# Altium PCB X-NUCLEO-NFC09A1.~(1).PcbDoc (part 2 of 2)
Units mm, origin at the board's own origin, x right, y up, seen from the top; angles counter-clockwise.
Board outline 103.96 x 54 mm, 4 copper layers (Top Layer, F2-GND, F3, Bottom Layer), stack 1.17 mm thick; 124 components, 76 nets, 282 pads, 390 vias.

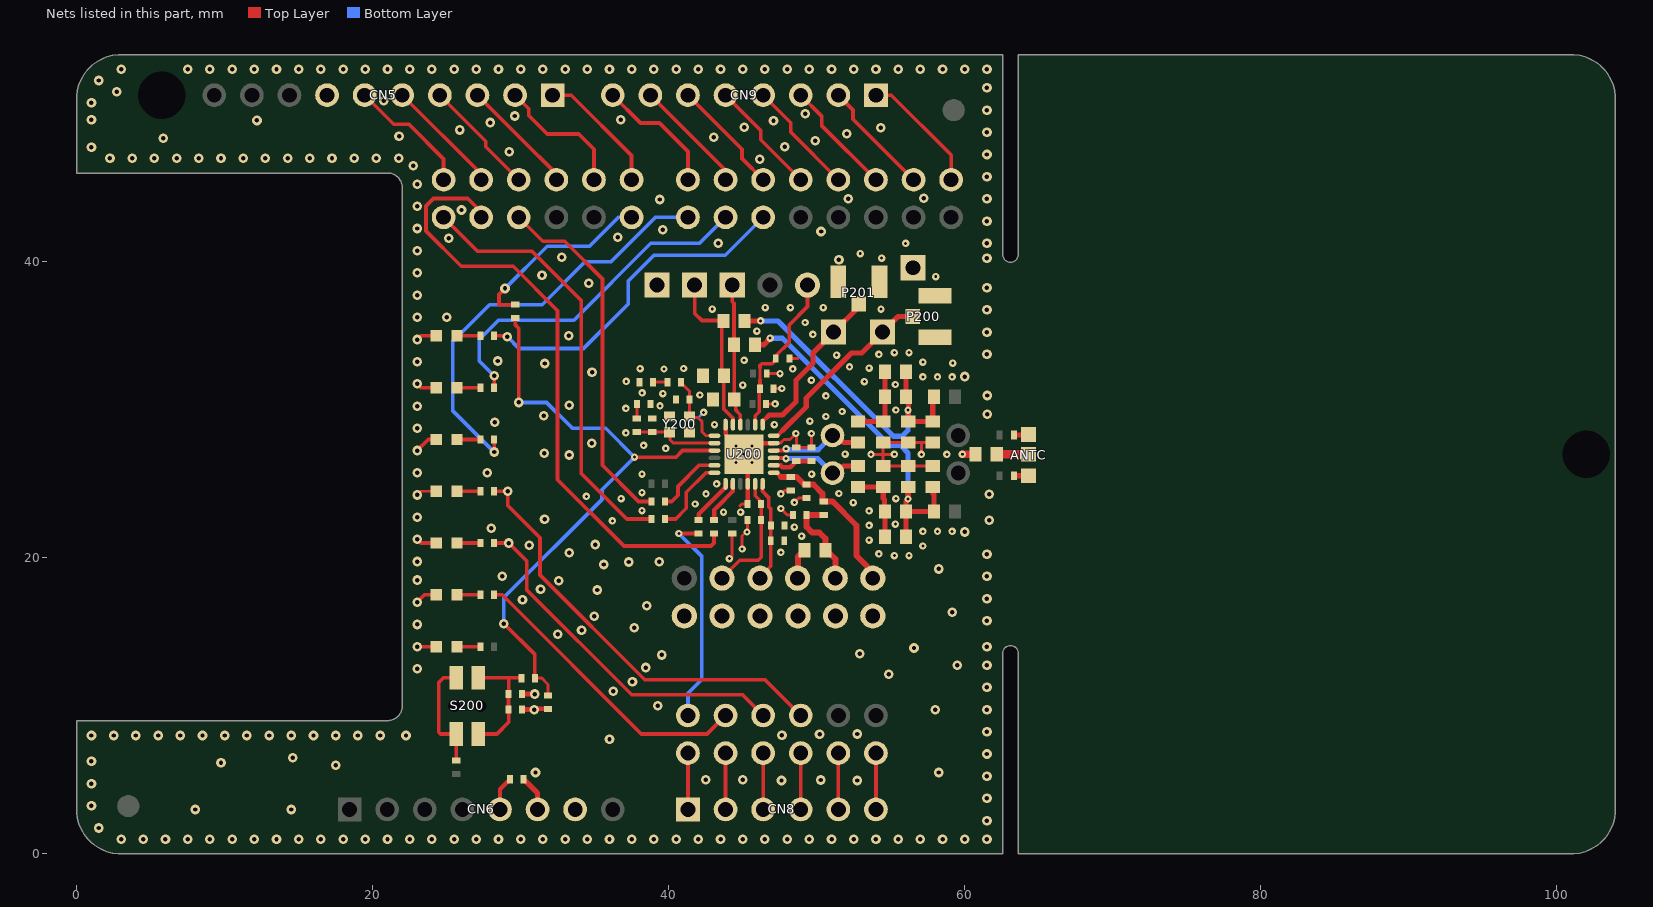
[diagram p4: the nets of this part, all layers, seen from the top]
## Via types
v1: diameter 0.65, hole 0.3, Top Layer to Bottom Layer, 272 vias
v2: diameter 0.5, hole 0.2, Top Layer to Bottom Layer, 108 vias
v3: diameter 1, hole 0.5, Top Layer to Bottom Layer, 10 vias

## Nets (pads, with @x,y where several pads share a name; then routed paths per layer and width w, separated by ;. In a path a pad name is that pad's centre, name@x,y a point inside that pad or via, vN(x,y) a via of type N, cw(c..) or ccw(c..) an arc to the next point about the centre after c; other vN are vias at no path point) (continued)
GND: C100.2 C200.2 C201.2 C202.2 C203.2 C204.2 C205.2 C206.2 C207.2 C208.2 C209.2 C210.2 C211.2 C212.2 C213.2 C214.2 C215.2 C216.1 C217.2 C218.2 C300.1 C304.2 C305.2 C306.2 C307.1 C308.1 C309.1 C313.2 CN5.7 CN6.6 CN6.7 LED100.2 LED101.2 LED102.2 LED103.2 LED104.2 LED105.2 LED106.2 P200.2 P200.3 P201.2 P201.3 R210.1 R212.2 R304.1 TP201.1 TP210.1 TP211.1 TP212.1 TP213.1 TP214.1 TP218.1 TP219.1 U200.4 U200.11 U200.18 U200.25 Y200.2 Y200.4 | length 48.4
  Top Layer w0.2: v1(23,24.25) 23.25,24.5 LED103.2@24.302,24.5 ; v2(44.1,19.95) 44.21,19.95 44.29,20.03 C212.2@44.29,21.636 ; 44.8,23.5 44.94,23.64 C210.2@45.333,23.64 ; v2(44.958,20.6) 44.958,21.481 45.323,21.846 C211.2@45.323,22.55 ; v2(45.09,27) U200.25@45.34,26.75 ; C200.2@46.572,30.4 v2(47.19,30.4) ; C201.2@46.622,32.45 v2(47.52,32.45) ; C202.2@47.067,31.43 47.63,31.43 v2(47.64,31.44) ; U200.11@47.09,27.75 47.54,27.75 47.79,28 48.19,28 v2(48.59,28.4) 48.62,28.37 C206.2@48.62,27.454 C207.2@49.64,27.454 v2(49.64,28.4) ; v2(47.579,23.332) 48.01,22.901 C215.2@48.401,22.901 ; v2(47.579,24.319) 47.811,24.551 C213.2@48.241,24.551 ; C203.2@48.147,33.468 48.154,33.475 48.735,33.475 48.74,33.48 ; v2(48.49,23.75) 48.783,24.043 C214.2@49.315,24.043 ; v2(53.665,26.997) 54.49,26.997 ; v2(55.24,27) 55.237,26.997 54.49,26.997 ; v2(57.065,26.997) 57.065,27.739 57.015,27.789 ; C305.2@57.84,26.211 C306.2@56.19,26.211 C304.2@54.49,26.211 54.49,26.997 ; C308.1@57.84,27.789 57.015,27.789 ; 54.49,26.997 C307.1@54.49,27.789 C309.1@56.19,27.789 57.015,27.789
  Top Layer w0.25: v1(23,14) LED100.2@24.302,14 ; v1(23,17) 23.5,17.5 LED101.2@24.302,17.5 ; v1(23,21.25) 23.25,21 LED102.2@24.302,21 ; v1(23,27.25) 23.75,28 LED104.2@24.302,28 ; v1(23,31.75) 23.25,31.5 LED105.2@24.302,31.5 ; v1(23,34.75) 23.25,35 LED106.2@24.302,35
  Top Layer w0.3: v1(30.925,9.75) 30.968,9.793 R212.2@31.85,9.793 ; U200.18@43.84,29 43.84,28.34 U200.25@44.33,27.85 ; C210.2@45.333,23.64 45.34,23.648 U200.4@45.34,25 U200.25@45.34,26.75 ; U200.25@45.34,27.75 U200.11@47.09,27.75
  Top Layer w0.35: C216.1@30.082,9.75 v1(30.925,9.75) ; R210.1@30.097,10.8 v1(30.94,10.8) ; C100.2@30.197,5.05 31.14,4.107 CN6.6@31.14,3
  Top Layer w0.5: v2(59.84,27) 60.732,27 R304.1@60.739,26.993
  Bottom Layer w0.2: 42.015,29.407 42.015,29.477 v2(42.362,29.824)
  other v1: 3,1 4.5,1 6,1 7.5,1 9,1 10.5,1 12,1 13.5,1 15,1 16.5,1 18,1 19.5,1 21,1 22.5,1 24,1 25.5,1 27,1 28.5,1 30,1 31.5,1 33,1 34.5,1 36,1 37.5,1 39,1 40.5,1 42,1 43.5,1 45,1 46.5,1 48,1 49.5,1 51,1 52.5,1 54,1 55.5,1 57,1 58.5,1 60,1 61.5,1 1.5,1.75 61.5,2.25 8,3 14.5,3 1,3.25 61.5,3.75 1,4.75 47.62,4.96 52.74,4.96 42.5,5 45,5 50.26,4.99 61.5,5.25 31,5.5 58.25,5.5 17.5,6 9.75,6.15 1,6.25 14.6,6.5 61.5,6.75 36,7.75 1,8 2.5,8 4,8 5.5,8 7,8 8.5,8 10,8 11.5,8 13,8 14.5,8 16,8 17.5,8 19,8 20.5,8 22.25,8 47.65,8.02 50.19,8.09 52.73,8.1 61.5,8.25 58,9.75 61.5,9.75 39.25,10 36.25,11 61.5,11.25 37.55,11.63 54.87,12.13 23,12.5 38.46,12.59 59.5,12.75 61.5,12.75 39.53,13.44 52.9,13.52 56.57,13.91 61.5,14 32.49,14.85 34.11,15.11 37.68,15.29 23,15.5 61.5,15.75 34.98,16.06 59.15,16.32 38.51,16.76 30.12,17.17 61.5,17.25 35.17,17.83 31.34,17.88 32.57,18.46 23,18.5 28.75,18.75 61.5,18.75 58.25,19.25 35.61,19.55 37.29,19.72 39.37,19.73 23,19.75 61.5,20.25 33.29,20.34 30.58,20.84 35.04,20.9 60,21.75 28,22 61.65,22.545 31.61,22.61 23,22.75 61.65,24.3 23,25.75 27.75,25.75 33.29,26.95 31.58,27.06 34.79,27.75 23,28.75 28.24,29.16 31.56,29.59 61.53,29.71 23,30.25 33.29,30.3 61.51,30.97 60,32.25 34.82,32.55 31.63,33.13 23,33.25 28.44,33.3 61.5,33.75 33.24,35 61.5,35.25 23,36.25 25,36.25 61.5,36.75 23,37.75 61.5,38.25 34.6,38.56 31.44,39.1 23,39.25 51.5,40.15 61.5,40.25 32.76,40.31 23,40.75 43.35,41.26 61.5,41.25 25.15,41.6 36.55,41.66 50.29,42.05 39.6,42.16 23,42.25 61.5,42.75 26,43.5 23,43.75 39.4,44.21 52.14,44.25 61.5,44.25 57.24,44.3 23,45.25 61.5,45.75 22.75,46.5 46.16,46.94 2.25,47 3.75,47 5.25,47 6.75,47 8.25,47 9.75,47 11.25,47 12.75,47 14.25,47 15.75,47 17.25,47 18.75,47 20.25,47 21.75,47 61.5,47.25 29.22,47.44 1,47.75 47.84,47.78 49.89,48.18 5.85,48.35 43.05,48.41 21.78,48.49 52.04,48.64 61.5,48.75 25.89,48.91 54.33,49.06 45.09,49.09 27.95,49.41 12.18,49.55 47.08,49.53 1,49.6 36.77,49.6 29.6,49.85 49.22,50 61.5,50.25 1,50.75 20.74,50.87 2.7,51.5 61.5,51.75 1.5,52.25 3,53 7.5,53 9,53 10.5,53 12,53 13.5,53 15,53 16.5,53 18,53 19.5,53 21,53 22.5,53 24,53 25.5,53 27,53 28.5,53 30,53 31.5,53 33,53 34.5,53 36,53 37.5,53 39,53 40.5,53 42,53 43.5,53 45,53 46.5,53 48,53 49.5,53 51,53 52.5,53 54,53 55.5,53 57,53 58.5,53 60,53 61.5,53
  other v2: 55.249,20.15 56.236,20.15 54.195,20.266 47.579,20.369 57.172,20.801 53.544,21.202 48.98,21.47 45.289,21.745 57.172,21.788 58.16,21.788 59.147,21.788 48.49,22.07 53.544,22.189 55.316,22.28 36.19,22.5 43.704,23.095 44.854,23.095 53.544,23.177 38.193,23.188 41.79,23.64 52.465,23.735 36.79,24 55.34,24.005 34.44,24.15 42.515,24.319 51.5,24.35 38.193,24.405 43.24,24.998 38.193,25.65 49.658,25.65 44.54,26.45 45.64,26.45 58.79,26.997 51.917,27.01 39.8,27.4 44.54,27.55 45.64,27.55 38.3,27.6 37.1,28.45 43.091,28.997 47.14,29 49.54,29.24 50.62,29.55 51.72,29.89 55.34,29.989 37.1,30.1 39.41,30.27 50.62,30.94 42.1,31 39.6,31.1 38.21,31.15 45,31.67 55.316,31.714 53.215,31.9 37.13,31.93 49.64,32 57.172,32.231 58.16,32.231 59.147,32.231 39.68,32.76 38.07,32.78 48.38,32.77 41.01,32.79 53.544,32.818 52.215,32.9 59.19,33.15 57.172,33.219 45.09,33.35 51.34,33.7 54.195,33.753 55.249,33.869 56.236,33.869 49.74,35.1 45.95,35.32 49.215,35.9 42.94,36.8 54.34,36.8 48.215,36.9 50.44,36.9 46.52,36.91 58.04,39 54.39,40.25 52.94,40.55 56,41.25
IRQ_200: R206.2 U200.1 | length 3.2
  Top Layer w0.3: R206.2@42.015,22.557 42.015,22.938 43.827,24.75 43.84,24.75 U200.1@43.84,25
IRQ_MCU: R206.1 ST15.2 | length 14.7
  Top Layer w0.25: v2(40.683,21.643) R206.1@42.015,21.643
  Bottom Layer w0.25: v2(40.683,21.643) 42.24,20.086 42.24,11.8 41.3,10.86 ST15.2@41.3,9.35
LED1: R101.2 ST16.2 | length 20
  Top Layer w0.25: R101.2@28.207,17.5 28.75,17.5 38.15,8.1 42.59,8.1 ST16.2@43.84,9.35
LED2: R102.2 ST17.2 | length 24.1
  Top Layer w0.25: R102.2@28.207,21 v1(29.2,21) 30.4,19.8 30.4,17.85 37.5,10.75 44.98,10.75 ST17.2@46.38,9.35
LED3: R103.2 ST18.2 | length 29.1
  Top Layer w0.25: R103.2@28.207,24.5 29.11,24.5 v1(29.12,24.49) 29.12,23.533 31.3,21.353 31.3,18.847 38.377,11.77 46.5,11.77 ST18.2@48.92,9.35
  Bottom Layer w0.25: v1(29.12,24.49) v1@29.15,24.52
LED4: R104.2 ST7.1 | length 28.8
  Top Layer w0.25: v1(28.2,27.15) 28.207,27.157 R104.2@28.207,28
  Bottom Layer w0.25: v1(28.2,27.15) 25.4,29.95 25.4,34.6 27.9,37.1 31.45,37.1 34.35,40 36.1,40 39.105,43.005 ST7.1@41.3,43.005
LED5: R105.2 ST8.1 | length 23.7
  Top Layer w0.25: R105.2@28.207,31.5 v1(28.207,32.293)
  Bottom Layer w0.25: v1(28.207,32.293) 27.2,33.3 27.2,34.75 28.5,36.05 33.592,36.05 38.792,41.25 42.085,41.25 ST8.1@43.84,43.005
LED6: R106.2 ST9.1 | length 23.1
  Top Layer w0.25: R106.2@28.207,35 29.04,35 v1(29.09,34.95)
  Bottom Layer w0.25: v1(29.09,34.95) 29.89,34.15 34.25,34.15 37.275,37.175 37.275,38.725 39,40.45 43.825,40.45 ST9.1@46.38,43.005
MISO_200: R207.2 U200.2 | length 3.4
  Top Layer w0.3: R207.2@43.065,22.557 43.065,23.236 ; U200.2@44.34,25.075 U200.2@44.34,25 44.34,24.511 43.29,23.461 ; 43.065,23.236 43.29,23.461 ; 43.065,23.236 43.29,23.461
MISO_MCU: R207.1 ST2.1 | length 42.1
  Top Layer w0.25: ST2.1@27.33,43.005 27.33,43.37 26.425,44.275 24.1,44.275 23.6,43.775 23.6,42.075 25.975,39.7 29.49,39.7 32.49,36.7 32.49,25.282 36.971,20.801 42.863,20.801 43.065,21.003 R207.1@43.065,21.643
MOSI_200: R204.2 U200.23 | length 4.7
  Top Layer w0.25: R204.2@39.762,23.811 40.201,23.811 40.625,24.235 40.625,24.823 42.051,26.25 U200.23@43.09,26.25
MOSI_MCU: R204.1 ST3.1 | length 24.3
  Top Layer w0.25: ST3.1@29.87,43.005 31.484,41.391 32.972,41.391 35.52,38.842 35.52,26.251 37.96,23.811 R204.1@38.848,23.811
NetANTC_1: ANTC.1 J304.2 | length 1
  Top Layer w0.35: J304.2@63.34,28.3 64.291,28.3 ANTC.1@64.316,28.325
NetANTC_2: ANTC.2 J300.2 | length 1
  Top Layer w0.35: J300.2@63.34,25.55 ANTC.2@64.316,25.55
NetANTC_3: ANTC.3 R304.2 | length 2.2
  Top Layer w0.6: R304.2@62.161,27 ANTC.3@64.316,27
NetC216_2: C216.2 R210.2 R211.2 S200.1 | length 8.3
  Top Layer w0.25: S200.1@27.14,8.1 28.39,8.1 29.183,8.893 29.183,9.75 C216.2@29.168,9.75 29.175,9.758 29.175,10.792 R210.2@29.168,10.8 ; S200.1@27.14,11.9 29.168,11.9 ; R210.2@29.183,10.8 29.183,11.9 30.018,11.9 R211.2@30.043,11.875
NetC217_1: C217.1 SB1.1 | length 1
  Top Layer w0.2: C217.1@38.937,31.87 SB1.1@39.913,31.87
NetC218_1: C218.1 SB2.2 | length 1
  Top Layer w0.2: SB2.2@37.84,29.417 37.841,29.419 37.841,30.399 C218.1@37.843,30.4
NetC301_1: C301.1 C303.1 C304.1 L300.1 | length 5.1
  Top Layer w0.35: L300.1@52.79,24.789 C304.1@54.49,24.789 54.49,24.025 54.587,23.928 54.587,23.141 C303.1@54.604,23.125 54.604,21.436 C301.1@54.615,21.425
NetC301_2: C301.2 C302.2 C303.2 C305.1 C306.1 R300.2 | length 24
  Top Layer w0.35: C302.2@45.826,34.4 46.433,34.4 46.85,34.817 v2(46.85,34.843) ; C303.2@56.026,23.1 C303.2@56.026,23.125 ; C301.2@56.037,21.425 56.037,23.114 C303.2@56.026,23.125 ; v2(56.165,23.975) 56.178,23.987 56.178,24.751 C306.1@56.215,24.789 ; v2@56.215,24 56.026,23.811 C303.2@56.026,23.125 ; C305.1@57.865,24.789 57.865,24.319 57.915,24.269 R300.2@57.915,23.125 C303.2@56.026,23.125 ; C305.1@57.89,24.789 C305.1@57.915,24.764
  Bottom Layer w0.35: v2(46.85,34.843) 47.677,34.843 54.91,27.61 55.648,27.61 56.165,27.093 v2(56.165,23.975)
NetC307_2: C307.2 C310.1 C311.1 L301.1 | length 5.1
  Top Layer w0.35: L301.1@52.79,29.211 C307.2@54.49,29.211 54.615,29.336 C310.1@54.615,30.875 C311.1@54.615,32.575
NetC308_2: C308.2 C309.2 C310.2 C311.2 C312.1 R301.2 | length 22.6
  Top Layer w0.35: C312.1@45.126,36.01 v2(46.21,36.01) ; C311.2@56.037,32.575 C310.2@56.037,30.875 56.19,30.722 56.19,29.975 C309.2@56.19,29.211 C308.2@57.84,29.211 57.84,30.8 R301.2@57.915,30.875
  Bottom Layer w0.35: v2(46.21,36.01) 47.38,36.01 55.18,28.21 55.76,28.21 56.165,28.615 v2(56.165,29.975)
NetCN5_1: CN5.1 ST6.2 | length 8.7
  Top Layer w0.25: CN5.1@32.156,51.26 33.414,51.26 37.49,47.184 ST6.2@37.49,45.545
NetCN5_2: CN5.2 ST5.2 | length 9.2
  Top Layer w0.25: CN5.2@29.616,51.26 30.538,50.338 30.538,49.887 31.79,48.635 33.915,48.635 34.95,47.6 ST5.2@34.95,45.545
NetCN5_3: CN5.3 ST4.2 | length 7.9
  Top Layer w0.25: CN5.3@27.076,51.26 29.953,48.383 32.41,45.926 ST4.2@32.41,45.545
NetCN5_4: CN5.4 ST3.2 | length 7.9
  Top Layer w0.25: CN5.4@24.536,51.26 27.645,48.151 27.645,47.77 ST3.2@29.87,45.545
NetCN5_5: CN5.5 ST2.2 | length 7.9
  Top Layer w0.25: CN5.5@21.996,51.26 27.33,45.926 ST2.2@27.33,45.545
NetCN5_6: CN5.6 ST1.2 | length 8.5
  Top Layer w0.25: CN5.6@19.456,51.26 21.424,49.292 22.453,49.292 24.79,46.955 ST1.2@24.79,45.545
NetCN8_1: CN8.1 ST15.1 | length 3.9
  Top Layer w0.25: CN8.1@41.25,3.05 CN8.1@41.3,3 41.3,6.71 41.25,6.76 ST15.1@41.3,6.81
NetCN8_2: CN8.2 ST16.1 | length 3.7
  Top Layer w0.25: CN8.2@43.84,3 ST16.1@43.84,6.71
NetCN8_3: CN8.3 ST17.1 | length 3.7
  Top Layer w0.25: CN8.3@46.38,3 ST17.1@46.38,6.71
NetCN8_4: CN8.4 ST18.1 | length 3.7
  Top Layer w0.25: CN8.4@48.92,3 ST18.1@48.92,6.71
NetCN8_5: CN8.5 ST19.1 | length 3.7
  Top Layer w0.25: CN8.5@51.46,3 ST19.1@51.46,6.71
NetCN8_6: CN8.6 ST20.1 | length 3.7
  Top Layer w0.25: CN8.6@54,3 ST20.1@54,6.71
NetCN9_1: CN9.1 ST14.2 | length 8.4
  Top Layer w0.25: CN9.1@54,51.26 55.029,51.26 59.08,47.209 ST14.2@59.08,45.545
NetCN9_2: CN9.2 ST13.2 | length 7.8
  Top Layer w0.25: CN9.2@51.46,51.26 52.455,50.265 52.455,49.63 ST13.2@56.54,45.545
NetCN9_3: CN9.3 ST12.2 | length 7.8
  Top Layer w0.25: CN9.3@48.92,51.26 50.33,49.85 50.33,49.215 ST12.2@54,45.545
NetCN9_4: CN9.4 ST11.2 | length 7.8
  Top Layer w0.25: CN9.4@46.38,51.26 48.24,49.4 48.24,48.765 ST11.2@51.46,45.545
NetCN9_5: CN9.5 ST10.2 | length 7.8
  Top Layer w0.25: CN9.5@43.84,51.26 46.225,48.875 46.225,48.24 ST10.2@48.92,45.545
NetCN9_6: CN9.6 ST9.2 | length 7.8
  Top Layer w0.25: CN9.6@41.3,51.26 44.95,47.61 44.95,46.975 ST9.2@46.38,45.545
NetCN9_7: CN9.7 ST8.2 | length 7.8
  Top Layer w0.25: CN9.7@38.76,51.26 43.84,46.18 ST8.2@43.84,45.545
NetCN9_8: CN9.8 ST7.2 | length 8.6
  Top Layer w0.25: CN9.8@36.22,51.26 38.1,49.38 39.37,49.38 41.3,47.45 ST7.2@41.3,45.545
NetLED100_1: LED100.1 R100.1 | length 1.6
  Top Layer w0.25: LED100.1@25.699,14 R100.1@27.293,14
NetLED101_1: LED101.1 R101.1 | length 1.6
  Top Layer w0.25: LED101.1@25.699,17.5 R101.1@27.293,17.5
NetLED102_1: LED102.1 R102.1 | length 1.6
  Top Layer w0.25: LED102.1@25.699,21 R102.1@27.293,21
NetLED103_1: LED103.1 R103.1 | length 1.6
  Top Layer w0.25: LED103.1@25.699,24.5 R103.1@27.293,24.5
NetLED104_1: LED104.1 R104.1 | length 1.6
  Top Layer w0.25: LED104.1@25.699,28 R104.1@27.293,28
NetLED105_1: LED105.1 R105.1 | length 1.6
  Top Layer w0.25: LED105.1@25.699,31.5 R105.1@27.293,31.5
NetLED106_1: LED106.1 R106.1 | length 1.6
  Top Layer w0.25: LED106.1@25.699,35 R106.1@27.293,35
NetR108_2: R108.2 ST6.1 | length 12.9
  Top Layer w0.25: v1(28.94,38.2) 28.54,37.8 28.54,37.107 R108.2@29.64,37.107
  Bottom Layer w0.25: v1(28.94,38.2) 31.79,41.05 34.65,41.05 36.605,43.005 ST6.1@37.49,43.005
NetR209_1: R209.1 S200.2 | length 7.7
  Top Layer w0.25: R209.1@25.64,6.307 S200.2@25.64,8.1 24.59,8.1 24.465,8.225 24.465,11.575 24.79,11.9 S200.2@25.64,11.9
RESET: R108.1 R211.1 R212.1 U200.21 | length 42
  Top Layer w0.2: R211.1@30.957,11.875 31.425,11.875 31.85,11.45 R212.1@31.85,10.707
  Top Layer w0.25: v1(28.86,15.56) 30.957,13.463 R211.1@30.957,11.875 ; R108.1@29.64,36.193 29.64,35.735 29.875,35.5 v1(29.875,30.5) ; v2(37.687,26.803) 40.488,26.803 40.935,27.25 U200.21@43.09,27.25
  Bottom Layer w0.25: v1(28.86,15.56) 28.86,17.32 35.49,23.95 35.49,24.606 v2(37.687,26.803) 35.74,28.75 33.5,28.75 31.75,30.5 v1(29.875,30.5)
RFI1: C300.2 C302.1 TP202.1 U200.16 | length 10.1
  Top Layer w0.25: TP202.1@44.289,38.427 44.289,37.305 44.404,37.19 C302.1@44.404,34.4 C302.1@44.404,34.075 ; C302.1@44.426,34.4 C300.2@44.426,30.7 44.526,30.6 44.526,29.989 44.54,29.975 ; 44.54,30 44.54,29.975 ; U200.16@44.84,28.925 U200.16@44.84,29 44.84,29.675 44.54,29.975
RFI2: C312.2 C313.1 TP203.1 U200.17 | length 11.1
  Top Layer w0.25: TP203.1@41.749,38.427 41.749,36.522 42.239,36.032 43.672,36.032 C312.2@43.704,36 ; C312.2@43.573,35.669 43.573,32.453 C313.1@43.726,32.3 43.726,30.046 44.34,29.433 U200.17@44.34,28.925
RFO1: J302.1 L300.2 U200.9 | length 6.2
  Top Layer w0.254: U200.9@47.015,26.75 U200.9@47.09,26.75 v2@47.69,26.75
  Top Layer w0.35: J302.1@51.065,25.725 51.321,25.725 51.807,26.211 L300.2@52.79,26.211 L300.2@52.815,26.211
  Bottom Layer w0.35: v2@47.94,26.723 50.067,26.723 J302.1@51.065,25.725
  other v2: 47.92,26.7
RFO2: J302.2 L301.2 U200.10 | length 6.5
  Top Layer w0.25: U200.10@47.015,27.25 47.816,27.25 47.938,27.372 v2@47.95,27.372
  Top Layer w0.35: J302.2@51.065,28.265 51.331,28.265 51.807,27.789 L301.2@52.815,27.789
  Bottom Layer w0.35: v2@47.95,27.372 48.022,27.3 50.1,27.3 J302.2@51.065,28.265
  other v2: 47.93,27.372
SCLK_200: R205.2 U200.24 | length 5.3
  Top Layer w0.25: R205.2@39.762,22.625 40.468,22.625 41.19,23.347 41.19,24.425 42.515,25.75 U200.24@43.09,25.75
SCLK_MCU: R205.1 ST1.1 | length 29.3
  Top Layer w0.25: ST1.1@24.79,43.005 27.075,40.72 30.758,40.72 34.09,37.388 34.09,25.7 37.165,22.625 R205.1@38.848,22.625
TAD1_200: P201.1 TP204.1 U200.13 | length 11.4
  Top Layer w0.28: U200.13@46.34,29 46.34,29.2 46.708,29.568
  Top Layer w0.35: 46.708,29.568 46.79,29.65 47.69,29.65 48.59,30.55 48.59,32 49.74,33.15 49.74,33.85 TP204.1@51.14,35.25 52.84,36.95 P201.1@52.84,37.15
TAD2_200: P200.1 TP200.1 U200.12 | length 13.2
  Top Layer w0.25: U200.12@47.015,28.25 47.021,28.256 U200.12@47.09,28.256 ; U200.12@47.09,28.25 47.34,28.25 47.69,28.6
  Top Layer w0.35: 47.69,28.6 49.29,30.2 49.29,30.8 52.34,33.85 53.04,33.85 TP200.1@54.44,35.25 55.49,36.3 P200.1@56.49,36.3
V_RF: C100.1 CN6.5 R208.2 TP215.1 | length 4.4
  Top Layer w0.3: CN6.5@28.6,3 28.6,4.367 C100.1@29.283,5.05
  Top Layer w0.4: TP215.1@48.725,18.625 48.725,20.08 R208.2@49.162,20.517
V_SHUNT: C215.1 L200.1 R208.1 TP216.1 | length 6.2
  Top Layer w0.4: L200.1@50.472,22.9 50.393,22.9 50.392,22.901 C215.1@49.315,22.901 49.315,22.08 49.693,21.703 50.187,21.703 50.585,21.305 R208.1@50.585,20.591 ; R208.1@50.585,20.517 R208.1@50.585,20.591 ; TP216.1@51.14,19.125 51.211,19.125 51.265,19.179 51.265,19.911 R208.1@50.585,20.591
VDD: C213.1 C214.1 L200.2 TP208.1 U200.7 | length 10.9
  Top Layer w0.28: U200.7@47.015,25.75 47.313,25.75 47.598,25.465
  Top Layer w0.4: 47.598,25.465 48.645,25.465 49.153,24.957 C214.1@49.315,24.957 49.776,24.957 50.393,24.34 50.393,23.814 L200.2@50.472,23.814 51.065,23.814 52.69,22.189 52.69,20.15 TP208.1@53.59,19.25 ; TP208.1@53.59,19.125 TP208.1@53.687,19.125
VDD_A: C202.1 C203.1 TP207.1 U200.14 | length 11.3
  Top Layer w0.21: 46.117,29.987 46.117,30.785 46.12,30.788 46.12,30.8 ; 46.16,32.034 46.16,32.062 46.163,32.065 46.163,32.825 46.165,32.827
  Top Layer w0.25: U200.14@45.84,28.925 U200.14@45.84,29 45.84,29.593 46.117,29.87 46.117,29.987 46.115,29.989 ; 46.12,30.8 46.12,31.397 C202.1@46.153,31.43 C202.1@46.133,31.45 ; C202.1@46.16,31.44 46.16,32.034 ; 46.165,32.861 46.163,32.863 46.163,32.993 46.28,33.11 46.97,33.11 47.233,33.373 C203.1@47.233,33.468 ; C203.1@47.234,33.482 47.262,33.509 47.262,33.684 48.135,34.557 48.135,35.736 49.38,36.98 TP207.1@49.38,38.425
VDD_AM: C208.1 C209.1 TP209.1 U200.6 | length 6.6
  Top Layer w0.25: TP209.1@46.217,19.125 46.59,19.125 46.893,19.428 C209.1@46.893,21.15 46.898,21.155 46.898,22.096 46.903,22.101 46.903,23.305 46.748,23.459 46.748,24.084 46.34,24.492 U200.6@46.34,25
VDD_D: C210.1 C211.1 TP206.1 U200.5 | length 8.4
  Top Layer w0.25: TP206.1@43.594,18.625 44.805,19.836 46.041,19.836 46.247,20.042 46.247,20.189 46.247,21.011 46.247,22.55 46.247,23.036 C210.1@46.247,23.64 46.247,23.792 45.84,24.199 U200.5@45.84,25
VDD_DR: C206.1 C207.1 U200.8 | length 2.8
  Top Layer w0.3: U200.8@47.09,26.25 47.554,26.25 47.682,26.122 48.202,26.122 C206.1@48.612,26.532 ; C206.1@48.62,26.54 C207.1@49.64,26.54
XTI: C204.1 SB1.2 U200.19 Y200.3 | length 5.2
  Top Layer w0.2: SB1.2@40.827,31.87 40.827,31.83 40.957,31.7 41.415,31.242 C204.1@41.415,30.7 Y200.3@41.415,29.55 41.491,29.474 41.973,29.474 42.259,29.188 42.259,28.506 42.515,28.25 U200.19@43.09,28.25
XTO: C205.1 SB2.1 U200.20 Y200.1 | length 5.9
  Top Layer w0.2: SB2.1@37.84,28.503 37.85,28.493 37.95,28.493 37.957,28.5 C205.1@38.89,28.5 38.892,28.498 Y200.1@40.065,28.498 40.1,28.463 40.1,27.965 40.315,27.75 U200.20@43.09,27.75
pads on no net: CN5.8 CN5.9 CN5.10 CN6.1 CN6.2 CN6.3 CN6.8 MIR1.1 MIR2.1 S200.MEC ST5.1 ST10.1 ST11.1 ST12.1 ST13.1 ST14.1 ST19.2 ST20.2
copper on no net: | length 80
  Top Layer w0.2: 5.25,5.7 5.25,6.95 ; 5.25,5.7 4,5.7 4,6.95 5.25,6.95 ; 5.25,5.7 5.25,6.95 ; 5.25,5.7 6.5,5.7 ; 5.25,6.95 6.5,6.95 ; 6.5,5.7 6.5,6.95 ; 6.5,5.7 6.5,6.95 ; 6.5,5.7 7.75,5.7 ; 6.5,6.95 7.75,6.95 ; 7.75,5.7 7.75,6.95 ; 7.75,5.7 7.75,6.95 ; 7.75,5.7 9,5.7 9,6.95 7.75,6.95
  F2-GND w0.2: 5.25,5.7 5.25,6.95 ; 5.25,5.7 4,5.7 4,6.95 5.25,6.95 ; 5.25,5.7 5.25,6.95 ; 5.25,5.7 6.5,5.7 ; 5.25,6.95 6.5,6.95 ; 6.5,5.7 6.5,6.95 ; 6.5,5.7 6.5,6.95 ; 6.5,5.7 7.75,5.7 ; 6.5,6.95 7.75,6.95 ; 7.75,5.7 7.75,6.95 ; 7.75,5.7 7.75,6.95 ; 7.75,5.7 9,5.7 9,6.95 7.75,6.95
  F3 w0.2: 5.25,5.7 4,5.7 4,6.95 5.25,6.95 ; 5.25,5.7 6.5,5.7 ; 5.25,5.7 5.25,6.95 ; 5.25,5.7 5.25,6.95 ; 5.25,6.95 6.5,6.95 ; 6.5,5.7 7.75,5.7 ; 6.5,5.7 6.5,6.95 ; 6.5,5.7 6.5,6.95 ; 6.5,6.95 7.75,6.95 ; 7.75,5.7 9,5.7 9,6.95 7.75,6.95 ; 7.75,5.7 7.75,6.95 ; 7.75,5.7 7.75,6.95
  Bottom Layer w0.2: 5.25,5.7 6.5,5.7 ; 5.25,5.7 5.25,6.95 ; 5.25,5.7 4,5.7 4,6.95 5.25,6.95 ; 5.25,5.7 5.25,6.95 ; 5.25,6.95 6.5,6.95 ; 6.5,5.7 7.75,5.7 ; 6.5,5.7 6.5,6.95 ; 6.5,5.7 6.5,6.95 ; 6.5,6.95 7.75,6.95 ; 7.75,5.7 9,5.7 9,6.95 7.75,6.95 ; 7.75,5.7 7.75,6.95 ; 7.75,5.7 7.75,6.95
  other v3: 65.532,25.55 68.02,25.555 94.779,25.555 97.3,25.559 65.541,27 69.282,27 65.532,28.325 66.779,28.445 96.02,28.445 98.541,28.45

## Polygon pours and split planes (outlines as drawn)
GND on F3 "GND_L03_P450" (solid, remove dead copper, pour order 14): 20.75,54.75 -1.5,54.75 -1.5,44.5 20.75,44.5 20.75,10.25 -1.25,10.25 -1.25,-0.75 12.05,-0.75 61.15,-0.75 62.173,-0.75 62.173,54.25 61.15,54.25 61.15,1.5 25.75,1.5 25.75,55 20.75,55
GND on F3 "GND_L03_P448" (solid, remove dead copper, pour order 448): 24,54.5 61.75,54.5 61.75,20.5 24,20.5
V_RF on F3 "V_RF_L03_P012" (solid, remove dead copper, pour order 12): 26.25,1.75 26.25,20.25 60.9,20.25 60.9,1.75
GND on Top Layer "remplissage-ST25R200" (solid, remove dead copper, pour order 453): 41.78,30.05 41.78,24.5 48.25,24.5 48.25,30
GND on Top Layer "TOP_GND" (solid, remove dead copper, pour order 450): 62.173,61.961 62.173,-8.042 -0.95,-8.042 -0.95,61.961
GND on F2-GND "GND" (solid, remove dead copper, pour order 10): 62.173,61.961 62.173,-8.042 -1.75,-8.042 -1.75,61.961
GND on Bottom Layer "BTM_GND" (solid, remove dead copper, pour order 452): 62.173,61.961 62.173,-8.042 -0.95,-8.042 -0.95,61.961

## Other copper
Top Layer:
  text "- TOP LAYER -" at 65.87,59.18 h1.5
  text ".text_ident_couches" at 4.82,58.98 h1.5
  text "1" at 4.5,5.95 h0.75
F2-GND:
  text "- LAYER 2 -" at 65.87,59.18 h1.5
  text ".text_ident_couches" at 4.82,58.98 h1.5
  text "2" at 5.6,5.95 h0.75
F3:
  text "- LAYER 3 -" at 40.62,59.18 h1.5
  text ".text_ident_couches" at 103.07,58.98 h1.5
  text "3" at 7.4,5.95 h0.75
Bottom Layer:
  text "- BOTTOM LAYER -" at 40.62,59.18 h1.5
  text ".text_ident_couches" at 103.07,58.98 h1.5
  text "4" at 8.7,5.95 h0.75

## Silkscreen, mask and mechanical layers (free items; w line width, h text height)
Top Overlay:
  drawing of 501 lines, arcs and shapes, not listed
  text "- TOP OVERLAY -" at 67.37,59.18 h1.5
  text ".text_ident_couches" at 4.82,58.98 h1.5
  text "2" at 27.88,47.17 h0.9 r90
  text "3" at 30.51,47.17 h0.9 r90
  text "5" at 35.6,47.17 h0.9 r90
  text "8" at 44.39,47.17 h0.9 r90
  text "9" at 47.02,47.17 h0.9 r90
  text "11" at 52.11,47.17 h0.9 r90
  text "13" at 57.19,47.17 h0.9 r90
  text "4" at 33.15,47.13 h0.9 r90
  text "10" at 49.41,47.05 h0.9 r90
  text "12" at 54.49,47.05 h0.9 r90
  text "VDD_A" at 47.74,40.612 h1.2
  text "RFI1" at 43.27,39.99 h1.2
  text "GND" at 38.07,39.864 h1.2
  text "AGD" at 45.79,39.534 h1.2
  text "RFI2" at 40.73,39.49 h1.2
  text "GND" at 57.57,39.364 h1.2
  text "LED6" at 23.75,36.05 h1.5
  text "TAD2" at 60.99,34.7 h1.5 r90
  text "LED5" at 23.5,32.55 h1.5
  text "life.augmented" at 81.089,30.408 h2.31 r90
  text "TAD1" at 53.24,30.4 h1.5 r90
  text "RFO2" at 51.826,30.2 h1.2 r90
  text "LED4" at 23.45,29.05 h1.5
  text "LED3" at 23.6,25.5 h1.5
  text "LED2" at 23.8,21.95 h1.5
  text "RFO1" at 53.53,21.202 h1.2 r90
  text "ST25" at 80.075,19.398 h1.56 r90
  text "LED1" at 23.8,18.5 h1.5
  text "VDD" at 55.59,15.4 h1.2 r90
  text "PWR OK" at 23.65,15.05 h1.5
  text "X-NUCLEO-NFC09A1" at 34.49,14.9 h2.5 r90
  text "V_RF" at 50.438,13 h1.2 r90
  text "GND" at 43.947,12.79 h1.2 r90
  text "GND" at 46.52,12.79 h1.2 r90
  text "GND" at 51.618,12.79 h1.2 r90
  text "GND" at 54.14,12.79 h1.2 r90
  text "GND" at 41.39,12.76 h1.2 r90
  text "GND" at 49.1,12.75 h1.2 r90
  text "VDD_D" at 45.238,12.175 h1.2 r90
  text "www.st.com/nucleo-nfc" at 72.35,11.95 h3.4 r90
  text "VDD_IO" at 42.68,11.75 h1.2 r90
  text "VDD_AM" at 47.838,11.125 h1.2 r90
  text "V_SHUNT" at 52.947,10.9 h1.15 r90
  text "16" at 43.09,10.75 h0.8
  text "17" at 45.336,10.743 h0.8
  text "18" at 48.14,10.75 h0.8
  text "19" at 50.39,10.75 h0.8
  text "RESET" at 23.563,7.79 h1.5 r90
  text "Nucleo" at 14,2.3 h1.2 r90
Bottom Overlay:
  drawing of 251 lines, arcs and shapes, not listed
  text "- BOTTOM OVERLAY -" at 40.62,59.18 h1.5
  text ".text_ident_couches" at 103.07,58.98 h1.5
  text "RoHS" at 50.825,12.425 h2.89
  text "Compliant" at 50.872,10.779 h1.64
  text "IC:8976A-NFC09A1" at 28.98,7.63 h5 r270
  text "FCCID:YCPNFC09A1" at 23.513,5.71 h5 r270
  text "FOR EVALUATION ONLY" at 33.96,5.71 h4.15 r270
Top Paste:
  lines w0.2: 63.09,38.714 62.989,38.714 62.802,38.637 62.659,38.494 62.582,38.307 62.582,38.206 62.582,29.792 62.659,29.605 62.802,29.462 62.989,29.385 63.191,29.385 63.378,29.462 63.521,29.605 63.598,29.792 63.598,38.307 63.521,38.494 63.378,38.637 63.191,38.714 63.09,38.714 ; 63.09,38.714 63.09,38.714 ; 63.598,40.484 63.598,40.383 63.521,40.196 63.378,40.053 63.191,39.976 63.09,39.976 62.989,39.976 62.802,40.053 62.659,40.196 62.582,40.383 62.582,40.484 62.582,54 2.803,54 2.413,53.949 2.032,53.847 1.669,53.696 1.328,53.499 1.015,53.259 0.737,52.981 0.497,52.669 0.3,52.328 0.149,51.964 0.047,51.583 -0.004,51.193 -0.004,50.996 0,46 21,46 cw(c21,45) 22,45 22,10 cw(c21,10) 21,9 0,9 0,2.803 0.051,2.413 0.153,2.034 0.304,1.67 0.5,1.33 0.74,1.018 1.018,0.74 1.33,0.5 1.67,0.304 2.034,0.153 2.413,0.051 2.803,0 62.582,0 62.582,13.669 62.659,13.856 62.802,13.999 62.989,14.076 63.191,14.076 63.378,13.999 63.521,13.856 63.598,13.669 63.598,0 101.154,0 101.544,0.051 101.924,0.153 102.287,0.304 102.628,0.5 102.94,0.74 103.218,1.018 103.457,1.33 103.654,1.67 103.804,2.034 103.906,2.413 103.957,2.803 103.957,51.197 103.906,51.587 103.804,51.966 103.654,52.33 103.457,52.67 103.218,52.982 102.94,53.26 102.628,53.5 102.287,53.696 101.924,53.847 101.544,53.949 101.154,54 63.598,54 63.598,40.484 ; 63.598,40.484 63.598,40.484 ; 62.582,15.745 62.659,15.558 62.802,15.415 62.989,15.338 63.191,15.338 63.378,15.415 63.521,15.558 63.598,15.745 63.598,24.133 63.521,24.32 63.378,24.463 63.191,24.54 62.989,24.54 62.802,24.463 62.659,24.32 62.582,24.133 62.582,15.745
  text "- TOP PASTE MASK -" at 67.37,59.18 h1.5
  text ".text_ident_couches" at 4.82,58.98 h1.5
Bottom Paste:
  text "- BOTTOM PASTE MASK -" at 40.62,59.18 h1.5
  text ".text_ident_couches" at 103.07,58.98 h1.5
Top Solder:
  lines w0.5: 20.948,46 0,46 -0.004,50.996 cw(c2.902,51.095) 2.803,54 62.582,54 62.582,40.484 ccw(c63.09,40.484) 63.598,40.484 ; 20.999,46 cw(c20.999,45) 21.999,45 ; 21,9 ccw(c21,10) 22,10 ; 21.048,9 0,9 0,2.803 ccw(c2.803,2.803) 2.803,0 62.582,0 62.582,13.568 cw(c63.09,13.568) 63.598,13.568 63.598,0 101.154,0 ccw(c101.154,2.803) 103.957,2.803 103.957,51.197 ccw(c101.154,51.197) 101.154,54 63.598,54 63.598,40.484 ; 22,9.952 22,44.948 ; 63.598,40.484 63.598,40.484 ; 62.582,15.846 ccw(c63.09,15.846) 63.598,15.846 63.598,24.031 ccw(c63.09,24.031) 62.582,24.031 62.582,15.846 ; 62.582,29.893 ccw(c63.09,29.893) 63.598,29.893 63.598,38.206 ccw(c63.09,38.206) 62.582,38.206 62.582,29.893
  text "- TOP SOLDER MASK -" at 67.37,59.18 h1.5
  text ".text_ident_couches" at 4.82,58.98 h1.5
Bottom Solder:
  lines w0.5: 20.999,46 cw(c20.999,45) 21.999,45 ; 21,9 ccw(c21,10) 22,10 ; 21,46 0,46 -0.004,50.996 cw(c2.902,51.095) 2.803,54 62.582,54 62.582,40.484 ccw(c63.09,40.484) 63.598,40.484 63.598,54 101.154,54 cw(c101.154,51.197) 103.957,51.197 103.957,2.803 cw(c101.154,2.803) 101.154,0 63.598,0 63.598,13.568 ccw(c63.09,13.568) 62.582,13.568 62.582,0 2.803,0 cw(c2.803,2.803) 0,2.803 0,9 21.048,9 ; 22,9.952 22,45 ; 62.582,15.846 ccw(c63.09,15.846) 63.598,15.846 63.598,24.032 ccw(c63.09,24.032) 62.582,24.032 62.582,15.846 ; 62.582,29.893 ccw(c63.09,29.893) 63.598,29.893 63.598,38.206 ccw(c63.09,38.206) 62.582,38.206 62.582,29.893
  text "- BOTTOM SOLDER MASK -" at 40.62,59.18 h1.5
  text ".text_ident_couches" at 103.07,58.98 h1.5
Top Assembly:
  region: 159,31 158,29 157,31
  lines w0.025: 62.611,27 65.541,27
  lines w0.15: 35.21,31.17 39.69,31.17 40.1,30.76 ; 42.75,24.75 42.98,24.75 43.33,24.4 47.21,24.4 47.7,23.91 48.83,23.91
  lines w0.17: 41.835,17.8 42.335,17.3 42.335,15.6 ; 44.375,17.8 44.875,17.3 44.875,15.6 ; 46.875,17.725 47.45,17.15 47.45,15.675 ; 47.025,30.425 47.375,30.775 50.425,30.775 ; 47.85,28.025 47.85,26.2 48.125,25.925 ; 48.625,22.325 49.275,21.675 49.5,21.675 ; 49.295,17.7 50.02,16.975 50.02,15.225 ; 51.835,17.7 52.56,16.975 52.56,15.225 ; 54.375,17.7 55.1,16.975 55.1,15.225 ; 64.75,27.35 69.825,27.35 70.875,26.3 70.875,25.475 ; 38.75,20.575 39.65,21.475 41.25,21.475 ; 38.75,20.575 38.75,17.075 37.7,16.025 32.9,16.025 31.4,17.525 31.4,20.8 32.05,21.45 37.875,21.45 38.75,20.575 ; 41.25,21.475 41.25,23.1 42.35,24.2 44.3,24.2 46.429,24.2 48.25,22.379 48.25,20.5 47.65,19.9 45.275,19.9 44.25,20.925 41.8,20.925 41.25,21.475 ; 65.75,14.975 65.75,23.975 67.25,25.475 74.5,25.475 78.075,21.9 78.075,15.25 75.025,12.2 68.525,12.2 65.75,14.975
  lines w0.2: 158,22 158,31 ; 149.323,32.5 150.521,31.5 150.021,31 166.771,31 166.021,32 166.521,32.5 149.323,32.5 ; 156,32.5 156,41.5 160,41.5 160,32.5 156,32.5
  text "CN5/CN6/CN8/CN9 ASSEMBLY DETAIL" at 130,44 h2
  text "TOP LAYER" at 162,37 h1.2
  text "DO NOT CUT" at 159,26 h1.2
  text "KEEP THE WHOLE PINS LENGTH" at 159,24 h1.2
  text "RoHS COMPLIANT PRODUCT" at 28.978,-6.848 h1.5
  text "TOP ASSEMBLY DRAWING" at 150.9,-105.55 h2
  text ".Reference" at 186.4,-130.55 h2
  text "01/01" at 244.4,-131.05 h2.1
Bottom Assembly:
  text "BOTTOM ASSEMBLY DRAWING" at -17.6,-105.55 h2
  text "02/02" at -119.1,-131.05 h2
  text ".Reference" at -60.1,-131.05 h2
Drill Drawing:
  drawing of 179 lines, arcs and shapes, not listed
  text "BOARD DESIGN CONCEPTION VALUES" at 170.68,111.62 h1.75
  text "SPECIFIED VALUES ARE MINIMUM. USED VALUES MAY BE LARGER" at 160.68,108.62 h1.4
  text "EXTERNAL" at 194.915,103.86 h1.4
  text "INTERNAL" at 215.87,103.86 h1.4
  text "LAYERS" at 194.915,101.32 h1.4
  text "LAYERS" at 215.87,101.32 h1.4
  text "FINISHED HOLE" at 193.9,97.45 h1.4
  text "FINISHED HOLE" at 216.15,97.45 h1.4
  text "PLATED HOLES" at 160.625,96.875 h1.4
  text "MIN. ANNULAR RING" at 160.625,94.335 h1.4
  text "0.30mm" at 199.995,94.335 h1.4
  text "0.30mm" at 222.245,94.335 h1.4
  text "+" at 196.82,93.7 h2.1
  text "+" at 219.07,93.7 h2.1
  text "DRILL HOLE" at 195.65,90.62 h1.4
  text "DRILL HOLE" at 217.9,90.62 h1.4
  text "VIA MINIMUM" at 159.99,89.89 h1.4
  text "0.15mm" at 200.15,87.62 h1.4
  text "0.15mm" at 222.4,87.62 h1.4
  text "ANNULAR RING" at 159.99,87.35 h1.4
  text "+" at 197.15,87.12 h2.1
  text "+" at 219.4,87.12 h2.1
  text "HOLE TO HOLE" at 159.99,82.905 h1.4
  text "0.35mm" at 197.4,81.95 h1.4
  text "TOP LAYER VIEW" at 38.911,80.922 h3
  text "MINIMUM CLEARANCE" at 159.99,80.365 h1.4
  text "MINIMUM TRACK WIDTH" at 160.045,71.235 h1.4
  text "0.15mm" at 215.29,71.235 h1.4
  text "MINIMUM CLEARANCE" at 159.41,66.79 h1.4
  text "0.125mm" at 215.29,65.52 h1.4
  text "BETWEEN COPPER PARTS" at 159.41,64.25 h1.4
  text "MINIMUM CLEARANCE BETWEEN :" at 159.735,61.22 h1.4
  text "NON-PLATED HOLES & COPPER PARTS :" at 159.735,58.22 h1.4
  text "FOR FULL BOARD OUTLINE AND ITS CUTOUTS DEFINITION, / REFER TO BOARD OUTLINE GERBER FILE" at 2.4,58.2 h2
  text "0.5mm" at 205.9,58.15 h1.4
  text "BOARD EDGE & COPPER PARTS :" at 159.735,55.22 h1.4
  text "0.50mm" at 197.735,55.22 h1.4
  text "SOLDER MASK EXPANSION FROM PAD EDGE :" at 159.735,52.22 h1.4
  text "0.05mm" at 212.735,52.22 h1.4
  text "VIAS FREE OF SOLDER MASK WITH 0.05mm EXPANSION" at 159.45,47.85 h1.4
  text "FROM VIA HOLE EDGE" at 159.35,45.25 h1.4
  text "MINIMUM SOLDER MASK SLIVER" at 160.07,40.005 h1.4
  text "0.10mm" at 219.125,40.005 h1.4
  text "SPECIFIC AND LOCAL VALUES" at 177.6,32.7 h1.75
  text "NONE" at 193.85,27.8 h1.4
  text "NOTES WHICH REFER TO IPC6012 SPECIFICATION /  IMPLY USE OF DOCUMENT LAST REVISION" at 162.15,6.95 h1.5
  text "1-" at 156.68,-0.05 h1.5
  text "MANUFACTURING ACCORDING TO" at 160.68,-0.05 h1.5
  text "IPC-6012 CLASS 2" at 200.68,-0.05 h1.5
  text "2-" at 156.68,-4.05 h1.5
  text "MATERIAL :" at 160.68,-4.05 h1.5
  text "FR4 TG 135 MINI - LOW CTE -" at 176.23,-4.15 h1.5
  text "3-" at 156.68,-8.05 h1.5
  text "HOLES PLATING :" at 160.68,-8.05 h1.5
  text "COPPER PLATING ACCORDING TO" at 183.68,-8.05 h1.5
  text "IPC-6012 RELATED TABLES" at 183.68,-11.05 h1.5
  text "4-" at 156.653,-14.298 h1.5
  text "COPPER WEIGHT : SEE LAYERS STACK-UP." at 162.368,-14.298 h1.5
  text "ACCORDING TO IPC-6012 RELATED TABLES:" at 162.368,-16.748 h1.5
  text "(INTERNAL , EXTERNAL STARTING FOIL)" at 162.368,-19.198 h1.5
  text "5-" at 156.653,-23.428 h1.5
  text "EXTERNAL LAYERS CHEMICAL PLATING:" at 162.368,-23.428 h1.5
  text "GOLD OVER NICKEL ACCORDING TO" at 162.68,-26.05 h1.5
  text "IPC6012 RELATED TABLE -  CODE ENIG" at 162.68,-29.05 h1.5
  text "6-" at 156.763,-34.398 h1.5
  text "SOLDER RESIST :" at 162.478,-34.398 h1.5
  text "LIQUID PHOTOIMAGEABLE" at 162.68,-37.05 h1.5
  text "TOP AND BOTTOM LAYERS" at 196.68,-37.05 h1.5
  text "LAYERS STACK-UP" at 86.57,-39.8 h2.1
  text "COLOR :" at 162.68,-40.05 h1.5
  text "BLUE" at 173.68,-40.05 h1.5
  text "Symbol" at -96.127,-44.031 h1.83
  text "Count" at -83.278,-44.031 h1.83
  text "Hole Size" at -68.042,-44.031 h1.83
  text "Plated" at -49.708,-44.031 h1.83
  text "Via/Pad" at -36.859,-44.031 h1.83
  text "TOP LAYER" at 91.57,-44.8 h1.75
  text "F1:17µ" at 73.82,-46.175 h1.4
  text "7-" at 156.763,-46.528 h1.5
  text "SILK SCREEN PRINTING" at 162.478,-46.528 h1.5
  text "TOP AND BOTTOM LAYERS" at 196.68,-47.05 h1.5
  text "108" at -83.278,-47.841 h1.52
  text "0.20mm" at -68.042,-47.841 h1.52
  text "PTH" at -49.708,-47.841 h1.52
  text "Via" at -36.859,-47.841 h1.52
  text "O" at -96.866,-48.095 h1.69
  text "EPOXYDE WHITE INK" at 162.68,-49.05 h1.5
  text "272" at -83.278,-51.651 h1.52
  text "0.30mm" at -68.042,-51.651 h1.52
  text "PTH" at -49.708,-51.651 h1.52
  text "Via" at -36.859,-51.651 h1.52
  text "F2:17µ" at 73.185,-51.89 h1.4
  text "S" at -96.866,-51.905 h1.69
  text "8-" at 157.398,-54.498 h1.5
  text "PACKING PAPER WITH CORROSION INHIBITOR" at 162.478,-54.498 h1.5
  text "10" at -83.278,-55.461 h1.52
  text "0.50mm" at -68.042,-55.461 h1.52
  text "PTH" at -49.708,-55.461 h1.52
  text "Via" at -36.859,-55.461 h1.52
  text "V" at -96.866,-55.715 h1.69
  text "F3:17µ" at 73.185,-56.97 h1.4
  text "96" at -83.278,-59.271 h1.52
  text "1.00mm" at -68.042,-59.271 h1.52
  text "PTH" at -49.708,-59.271 h1.52
  text "Pad" at -36.859,-59.271 h1.52
  text "B" at -96.866,-59.525 h1.69
  text "9-" at 157.448,-60.848 h1.5
  text "RoHS COMPLIANT PRODUCT" at 162.528,-60.848 h1.5
  text "1.2 +/-10%" at 131.15,-61.25 h1.4 r90
  text "F4:17µ" at 73.185,-62.685 h1.4
  text "2" at -83.278,-63.081 h1.52
  text "0.80mm" at -68.042,-63.081 h1.52
  text "NPTH" at -49.708,-63.081 h1.52
  text "Pad" at -36.859,-63.081 h1.52
  text "A" at -96.866,-63.335 h1.69
  text "2" at -83.278,-66.891 h1.52
  text "3.20mm" at -68.042,-66.891 h1.52
  text "NPTH" at -49.708,-66.891 h1.52
  text "Pad" at -36.859,-66.891 h1.52
  text "X" at -96.866,-67.145 h1.69
  text "BOTTOM LAYER" at 88.57,-67.8 h1.75
  text "490 Total" at -83.278,-70.701 h1.52
  text "Hole Size shall be taken as follow : / - PTH PAD : Finished Size / - PTH VIA : Drill Size / - Any NPTH : Drill Size" at -93.962,-85.92 h1.5
  text "Hole Size Tolerance (unless otherwise specified):" at -93.859,-91.928 h1.5
  text "PTH <1.6mm: +0.1/-0.05" at -87.65,-94.3 h1.5
  text "PTH >1.6mm: +0.15/-0.1" at -87.7,-97.24 h1.5
  text "NPTH: +/-0.1" at -87.7,-100.69 h1.5
  text "DRILL DRAWING" at 156.4,-105.55 h2
  text "Vias: No requirement regarding to the finished hole size" at -87.92,-106.62 h1.5
  text "WARNING: / Drill letters are only intended to provide / an overview of the drill map. They may not / match with the exact holes location. / They shall not be used for drill process." at -87.2,-124.7 h1.5
  text ".Reference" at 186.9,-131.05 h2.1
  text "01/01" at 245.4,-131.05 h2.1
Cartouche Top:
  drawing of 442 lines, arcs and shapes, not listed
  text "DATE" at 81.9,-91.05 h1.05
  text "EVOLUTION" at 109.9,-91.05 h1.05
  text "DESIGNER" at 144.9,-91.05 h1.05
  text "REV" at 162.9,-91.05 h1.05
  text "DATE" at 171.9,-91.05 h1.05
  text "EVOLUTION" at 197.9,-91.05 h1.05
  text "DESIGNER" at 233.9,-91.05 h1.05
  text "REV" at 251.597,-91.251 h1.05
  text "TITLE :" at 83.537,-98.151 h2.1
  text ".Title" at 157.224,-98.766 h2.1
  text "GENERAL TOL." at 235.9,-99.05 h1.4
  text "+/- 0,2" at 237.9,-105.05 h1.75
  text "DOCUMENT :" at 83.537,-105.771 h2.1
  text "CHECKED" at 183.9,-111.05 h1.05
  text "APPROVED" at 211.9,-111.05 h1.05
  text "SCALE :" at 107.9,-112.05 h1.05
  text "DRAWN :" at 134.9,-112.05 h1.4
  text "BE TECH" at 157.9,-112.05 h1.4
  text "1/1" at 119.721,-112.766 h2.1
  text "DATE :" at 135.9,-116.05 h1.4
  text "'.date_dossier'" at 157.9,-116.05 h1.4
  text "UNIT. :" at 108.9,-117.05 h1.05
  text "mm" at 120.9,-117.05 h1.4
  text "DOCUMENT REFERENCE" at 186.9,-121.05 h1.4
  text "ST MICROELECTRONICS" at 103.32,-122.6 h1.75
  text "PART NUMBER" at 179.9,-125.05 h1.4
  text "FORMAT" at 228.9,-125.05 h1.4
  text "SHEET" at 246.9,-125.05 h1.4
  text "SKY SOPHIA BATIMENT B" at 105.09,-125.68 h1.4
  text "776 RUE ALBERT CAQUOT" at 105.09,-128.68 h1.4
  text "3" at 232.9,-131.05 h2.1
  text "SOPHIA ANTIPOLIS" at 104.983,-131.579 h1.4
  text "06410 BIOT" at 105.21,-134.49 h1.4
  text ".Revision" at 247.5,-137 h1.5
  text "REV" at 252.9,-137.05 h1.4
  text "FRANCE" at 105.483,-137.579 h1.4
Cartouche bottom:
  drawing of 442 lines, arcs and shapes, not listed
  text "DESIGNER" at -107.466,-91.05 h1.05
  text "EVOLUTION" at -71.466,-91.05 h1.05
  text "DATE" at -45.466,-91.05 h1.05
  text "REV" at -36.466,-91.05 h1.05
  text "DESIGNER" at -18.466,-91.05 h1.05
  text "EVOLUTION" at 16.534,-91.05 h1.05
  text "DATE" at 44.534,-91.05 h1.05
  text "REV" at -125.163,-91.251 h1.05
  text "TITLE :" at 42.897,-98.151 h2.1
  text ".Title" at -30.79,-98.766 h2.1
  text "GENERAL TOL." at -109.466,-99.05 h1.4
  text "+/- 0,2" at -111.466,-105.05 h1.75
  text "DOCUMENT :" at 42.897,-105.771 h2.1
  text "APPROVED" at -85.466,-111.05 h1.05
  text "CHECKED" at -57.466,-111.05 h1.05
  text "BE TECH" at -31.466,-112.05 h1.4
  text "DRAWN :" at -8.466,-112.05 h1.4
  text "SCALE :" at 18.534,-112.05 h1.05
  text "1/1" at 6.713,-112.766 h2.1
  text "'.date_dossier'" at -31.466,-116.05 h1.4
  text "DATE :" at -9.466,-116.05 h1.4
  text "mm" at 5.534,-117.05 h1.4
  text "UNIT. :" at 17.534,-117.05 h1.05
  text "DOCUMENT REFERENCE" at -60.466,-121.05 h1.4
  text "ST MICROELECTRONICS" at 23.17,-122.56 h1.75
  text "SHEET" at -120.466,-125.05 h1.4
  text "FORMAT" at -102.466,-125.05 h1.4
  text "PART NUMBER" at -53.466,-125.05 h1.4
  text "SKY SOPHIA BATIMENT B" at 21.4,-125.64 h1.4
  text "776 RUE ALBERT CAQUOT" at 21.4,-128.64 h1.4
  text "3" at -106.466,-131.05 h2.1
  text "SOPHIA ANTIPOLIS" at 21.507,-131.539 h1.4
  text "06410 BIOT" at 21.28,-134.45 h1.4
  text ".Revision" at -121.2,-137 h1.5
  text "REV" at -126.466,-137.05 h1.4
  text "FRANCE" at 21.007,-137.539 h1.4
Board:
  lines w0.2: 63.09,38.714 63.191,38.714 63.378,38.637 63.521,38.494 63.598,38.307 63.598,29.893 63.598,29.792 63.521,29.605 63.378,29.462 63.191,29.385 62.989,29.385 62.802,29.462 62.659,29.605 62.582,29.792 62.582,38.206 62.582,38.307 62.659,38.494 62.802,38.637 62.989,38.714 63.09,38.714 ; 63.09,38.714 63.09,38.714 ; 63.598,40.484 63.598,40.484 ; 63.598,40.484 63.598,40.383 63.521,40.196 63.378,40.053 63.191,39.976 63.09,39.976 62.989,39.976 62.802,40.053 62.659,40.196 62.582,40.383 62.582,40.484 62.582,54 2.803,54 2.413,53.949 2.032,53.847 1.669,53.696 1.328,53.499 1.015,53.259 0.737,52.981 0.497,52.669 0.3,52.328 0.149,51.964 0.047,51.583 -0.004,51.193 -0.004,50.996 0,46 21,46 cw(c21,45) 22,45 22,10 cw(c21,10) 21,9 0,9 0,2.803 0.051,2.413 0.153,2.034 0.304,1.67 0.5,1.33 0.74,1.018 1.018,0.74 1.33,0.5 1.67,0.304 2.034,0.153 2.413,0.051 2.803,0 62.582,0 62.582,13.669 62.659,13.856 62.802,13.999 62.989,14.076 63.191,14.076 63.378,13.999 63.521,13.856 63.598,13.669 63.598,0 101.154,0 101.544,0.051 101.924,0.153 102.287,0.304 102.628,0.5 102.94,0.74 103.218,1.018 103.457,1.33 103.654,1.67 103.804,2.034 103.906,2.413 103.957,2.803 103.957,51.197 103.906,51.587 103.804,51.966 103.654,52.33 103.457,52.67 103.218,52.982 102.94,53.26 102.628,53.5 102.287,53.696 101.924,53.847 101.544,53.949 101.154,54 63.598,54 63.598,40.484 ; 62.582,15.745 62.659,15.558 62.802,15.415 62.989,15.338 63.191,15.338 63.378,15.415 63.521,15.558 63.598,15.745 63.598,24.133 63.521,24.32 63.378,24.463 63.191,24.54 62.989,24.54 62.802,24.463 62.659,24.32 62.582,24.133 62.582,15.745

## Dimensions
-0.5,-0.5 to -7,-7 on Drill Drawing
0,2.803 to 103.957,2.803 on Drill Drawing
2.803,0 to 2.803,54 on Drill Drawing
101.154,0 to 102,27 on Drill Drawing
103.957,2.803 to 102,27 on Drill Drawing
